VERSION 5.7 ;
BUSBITCHARS "[]" ;
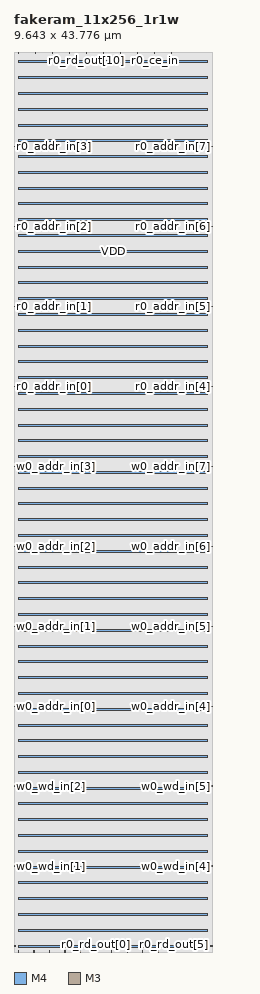
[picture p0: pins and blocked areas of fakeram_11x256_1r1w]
MACRO fakeram_11x256_1r1w
  FOREIGN fakeram_11x256_1r1w 0 0 ;
  SYMMETRY X Y R90 ;
  SIZE 9.643 BY 43.776 ;
  CLASS BLOCK ;
  PIN w0_wd_in[0]
    DIRECTION INPUT ;
    USE SIGNAL ;
    SHAPE ABUTMENT ;
    PORT
      LAYER M4 ;
      RECT 0.000 0.276 0.072 0.300 ;
    END
  END w0_wd_in[0]
  PIN w0_wd_in[1]
    DIRECTION INPUT ;
    USE SIGNAL ;
    SHAPE ABUTMENT ;
    PORT
      LAYER M4 ;
      RECT 0.000 4.164 0.072 4.188 ;
    END
  END w0_wd_in[1]
  PIN w0_wd_in[2]
    DIRECTION INPUT ;
    USE SIGNAL ;
    SHAPE ABUTMENT ;
    PORT
      LAYER M4 ;
      RECT 0.000 8.052 0.072 8.076 ;
    END
  END w0_wd_in[2]
  PIN w0_wd_in[3]
    DIRECTION INPUT ;
    USE SIGNAL ;
    SHAPE ABUTMENT ;
    PORT
      LAYER M4 ;
      RECT 9.571 0.276 9.643 0.300 ;
    END
  END w0_wd_in[3]
  PIN w0_wd_in[4]
    DIRECTION INPUT ;
    USE SIGNAL ;
    SHAPE ABUTMENT ;
    PORT
      LAYER M4 ;
      RECT 9.571 4.164 9.643 4.188 ;
    END
  END w0_wd_in[4]
  PIN w0_wd_in[5]
    DIRECTION INPUT ;
    USE SIGNAL ;
    SHAPE ABUTMENT ;
    PORT
      LAYER M4 ;
      RECT 9.571 8.052 9.643 8.076 ;
    END
  END w0_wd_in[5]
  PIN w0_wd_in[6]
    DIRECTION OUTPUT ;
    USE SIGNAL ;
    SHAPE ABUTMENT ;
    PORT
      LAYER M3 ;
      RECT 0.207 0.000 0.225 0.054 ;
    END
  END w0_wd_in[6]
  PIN w0_wd_in[7]
    DIRECTION OUTPUT ;
    USE SIGNAL ;
    SHAPE ABUTMENT ;
    PORT
      LAYER M3 ;
      RECT 0.963 0.000 0.981 0.054 ;
    END
  END w0_wd_in[7]
  PIN w0_wd_in[8]
    DIRECTION OUTPUT ;
    USE SIGNAL ;
    SHAPE ABUTMENT ;
    PORT
      LAYER M3 ;
      RECT 1.719 0.000 1.737 0.054 ;
    END
  END w0_wd_in[8]
  PIN w0_wd_in[9]
    DIRECTION OUTPUT ;
    USE SIGNAL ;
    SHAPE ABUTMENT ;
    PORT
      LAYER M3 ;
      RECT 2.475 0.000 2.493 0.054 ;
    END
  END w0_wd_in[9]
  PIN w0_wd_in[10]
    DIRECTION OUTPUT ;
    USE SIGNAL ;
    SHAPE ABUTMENT ;
    PORT
      LAYER M3 ;
      RECT 3.231 0.000 3.249 0.054 ;
    END
  END w0_wd_in[10]
  PIN r0_rd_out[0]
    DIRECTION OUTPUT ;
    USE SIGNAL ;
    SHAPE ABUTMENT ;
    PORT
      LAYER M3 ;
      RECT 3.987 0.000 4.005 0.054 ;
    END
  END r0_rd_out[0]
  PIN r0_rd_out[1]
    DIRECTION OUTPUT ;
    USE SIGNAL ;
    SHAPE ABUTMENT ;
    PORT
      LAYER M3 ;
      RECT 4.743 0.000 4.761 0.054 ;
    END
  END r0_rd_out[1]
  PIN r0_rd_out[2]
    DIRECTION OUTPUT ;
    USE SIGNAL ;
    SHAPE ABUTMENT ;
    PORT
      LAYER M3 ;
      RECT 5.499 0.000 5.517 0.054 ;
    END
  END r0_rd_out[2]
  PIN r0_rd_out[3]
    DIRECTION OUTPUT ;
    USE SIGNAL ;
    SHAPE ABUTMENT ;
    PORT
      LAYER M3 ;
      RECT 6.255 0.000 6.273 0.054 ;
    END
  END r0_rd_out[3]
  PIN r0_rd_out[4]
    DIRECTION OUTPUT ;
    USE SIGNAL ;
    SHAPE ABUTMENT ;
    PORT
      LAYER M3 ;
      RECT 7.011 0.000 7.029 0.054 ;
    END
  END r0_rd_out[4]
  PIN r0_rd_out[5]
    DIRECTION OUTPUT ;
    USE SIGNAL ;
    SHAPE ABUTMENT ;
    PORT
      LAYER M3 ;
      RECT 7.767 0.000 7.785 0.054 ;
    END
  END r0_rd_out[5]
  PIN r0_rd_out[6]
    DIRECTION OUTPUT ;
    USE SIGNAL ;
    SHAPE ABUTMENT ;
    PORT
      LAYER M3 ;
      RECT 0.207 43.722 0.225 43.776 ;
    END
  END r0_rd_out[6]
  PIN r0_rd_out[7]
    DIRECTION OUTPUT ;
    USE SIGNAL ;
    SHAPE ABUTMENT ;
    PORT
      LAYER M3 ;
      RECT 1.035 43.722 1.053 43.776 ;
    END
  END r0_rd_out[7]
  PIN r0_rd_out[8]
    DIRECTION OUTPUT ;
    USE SIGNAL ;
    SHAPE ABUTMENT ;
    PORT
      LAYER M3 ;
      RECT 1.863 43.722 1.881 43.776 ;
    END
  END r0_rd_out[8]
  PIN r0_rd_out[9]
    DIRECTION OUTPUT ;
    USE SIGNAL ;
    SHAPE ABUTMENT ;
    PORT
      LAYER M3 ;
      RECT 2.691 43.722 2.709 43.776 ;
    END
  END r0_rd_out[9]
  PIN r0_rd_out[10]
    DIRECTION OUTPUT ;
    USE SIGNAL ;
    SHAPE ABUTMENT ;
    PORT
      LAYER M3 ;
      RECT 3.519 43.722 3.537 43.776 ;
    END
  END r0_rd_out[10]
  PIN w0_addr_in[0]
    DIRECTION INPUT ;
    USE SIGNAL ;
    SHAPE ABUTMENT ;
    PORT
      LAYER M4 ;
      RECT 0.000 11.940 0.072 11.964 ;
    END
  END w0_addr_in[0]
  PIN w0_addr_in[1]
    DIRECTION INPUT ;
    USE SIGNAL ;
    SHAPE ABUTMENT ;
    PORT
      LAYER M4 ;
      RECT 0.000 15.828 0.072 15.852 ;
    END
  END w0_addr_in[1]
  PIN w0_addr_in[2]
    DIRECTION INPUT ;
    USE SIGNAL ;
    SHAPE ABUTMENT ;
    PORT
      LAYER M4 ;
      RECT 0.000 19.716 0.072 19.740 ;
    END
  END w0_addr_in[2]
  PIN w0_addr_in[3]
    DIRECTION INPUT ;
    USE SIGNAL ;
    SHAPE ABUTMENT ;
    PORT
      LAYER M4 ;
      RECT 0.000 23.604 0.072 23.628 ;
    END
  END w0_addr_in[3]
  PIN w0_addr_in[4]
    DIRECTION INPUT ;
    USE SIGNAL ;
    SHAPE ABUTMENT ;
    PORT
      LAYER M4 ;
      RECT 9.571 11.940 9.643 11.964 ;
    END
  END w0_addr_in[4]
  PIN w0_addr_in[5]
    DIRECTION INPUT ;
    USE SIGNAL ;
    SHAPE ABUTMENT ;
    PORT
      LAYER M4 ;
      RECT 9.571 15.828 9.643 15.852 ;
    END
  END w0_addr_in[5]
  PIN w0_addr_in[6]
    DIRECTION INPUT ;
    USE SIGNAL ;
    SHAPE ABUTMENT ;
    PORT
      LAYER M4 ;
      RECT 9.571 19.716 9.643 19.740 ;
    END
  END w0_addr_in[6]
  PIN w0_addr_in[7]
    DIRECTION INPUT ;
    USE SIGNAL ;
    SHAPE ABUTMENT ;
    PORT
      LAYER M4 ;
      RECT 9.571 23.604 9.643 23.628 ;
    END
  END w0_addr_in[7]
  PIN r0_addr_in[0]
    DIRECTION INPUT ;
    USE SIGNAL ;
    SHAPE ABUTMENT ;
    PORT
      LAYER M4 ;
      RECT 0.000 27.492 0.072 27.516 ;
    END
  END r0_addr_in[0]
  PIN r0_addr_in[1]
    DIRECTION INPUT ;
    USE SIGNAL ;
    SHAPE ABUTMENT ;
    PORT
      LAYER M4 ;
      RECT 0.000 31.380 0.072 31.404 ;
    END
  END r0_addr_in[1]
  PIN r0_addr_in[2]
    DIRECTION INPUT ;
    USE SIGNAL ;
    SHAPE ABUTMENT ;
    PORT
      LAYER M4 ;
      RECT 0.000 35.268 0.072 35.292 ;
    END
  END r0_addr_in[2]
  PIN r0_addr_in[3]
    DIRECTION INPUT ;
    USE SIGNAL ;
    SHAPE ABUTMENT ;
    PORT
      LAYER M4 ;
      RECT 0.000 39.156 0.072 39.180 ;
    END
  END r0_addr_in[3]
  PIN r0_addr_in[4]
    DIRECTION INPUT ;
    USE SIGNAL ;
    SHAPE ABUTMENT ;
    PORT
      LAYER M4 ;
      RECT 9.571 27.492 9.643 27.516 ;
    END
  END r0_addr_in[4]
  PIN r0_addr_in[5]
    DIRECTION INPUT ;
    USE SIGNAL ;
    SHAPE ABUTMENT ;
    PORT
      LAYER M4 ;
      RECT 9.571 31.380 9.643 31.404 ;
    END
  END r0_addr_in[5]
  PIN r0_addr_in[6]
    DIRECTION INPUT ;
    USE SIGNAL ;
    SHAPE ABUTMENT ;
    PORT
      LAYER M4 ;
      RECT 9.571 35.268 9.643 35.292 ;
    END
  END r0_addr_in[6]
  PIN r0_addr_in[7]
    DIRECTION INPUT ;
    USE SIGNAL ;
    SHAPE ABUTMENT ;
    PORT
      LAYER M4 ;
      RECT 9.571 39.156 9.643 39.180 ;
    END
  END r0_addr_in[7]
  PIN w0_we_in
    DIRECTION INPUT ;
    USE SIGNAL ;
    SHAPE ABUTMENT ;
    PORT
      LAYER M3 ;
      RECT 4.347 43.722 4.365 43.776 ;
    END
  END w0_we_in
  PIN w0_ce_in
    DIRECTION INPUT ;
    USE SIGNAL ;
    SHAPE ABUTMENT ;
    PORT
      LAYER M3 ;
      RECT 5.175 43.722 5.193 43.776 ;
    END
  END w0_ce_in
  PIN w0_clk
    DIRECTION INPUT ;
    USE SIGNAL ;
    SHAPE ABUTMENT ;
    PORT
      LAYER M3 ;
      RECT 6.003 43.722 6.021 43.776 ;
    END
  END w0_clk
  PIN r0_ce_in
    DIRECTION INPUT ;
    USE SIGNAL ;
    SHAPE ABUTMENT ;
    PORT
      LAYER M3 ;
      RECT 6.831 43.722 6.849 43.776 ;
    END
  END r0_ce_in
  PIN r0_clk
    DIRECTION INPUT ;
    USE SIGNAL ;
    SHAPE ABUTMENT ;
    PORT
      LAYER M3 ;
      RECT 7.659 43.722 7.677 43.776 ;
    END
  END r0_clk
  PIN VSS
    DIRECTION INOUT ;
    USE GROUND ;
    PORT
      LAYER M4 ;
      RECT 0.216 0.240 9.427 0.336 ;
      RECT 0.216 1.008 9.427 1.104 ;
      RECT 0.216 1.776 9.427 1.872 ;
      RECT 0.216 2.544 9.427 2.640 ;
      RECT 0.216 3.312 9.427 3.408 ;
      RECT 0.216 4.080 9.427 4.176 ;
      RECT 0.216 4.848 9.427 4.944 ;
      RECT 0.216 5.616 9.427 5.712 ;
      RECT 0.216 6.384 9.427 6.480 ;
      RECT 0.216 7.152 9.427 7.248 ;
      RECT 0.216 7.920 9.427 8.016 ;
      RECT 0.216 8.688 9.427 8.784 ;
      RECT 0.216 9.456 9.427 9.552 ;
      RECT 0.216 10.224 9.427 10.320 ;
      RECT 0.216 10.992 9.427 11.088 ;
      RECT 0.216 11.760 9.427 11.856 ;
      RECT 0.216 12.528 9.427 12.624 ;
      RECT 0.216 13.296 9.427 13.392 ;
      RECT 0.216 14.064 9.427 14.160 ;
      RECT 0.216 14.832 9.427 14.928 ;
      RECT 0.216 15.600 9.427 15.696 ;
      RECT 0.216 16.368 9.427 16.464 ;
      RECT 0.216 17.136 9.427 17.232 ;
      RECT 0.216 17.904 9.427 18.000 ;
      RECT 0.216 18.672 9.427 18.768 ;
      RECT 0.216 19.440 9.427 19.536 ;
      RECT 0.216 20.208 9.427 20.304 ;
      RECT 0.216 20.976 9.427 21.072 ;
      RECT 0.216 21.744 9.427 21.840 ;
      RECT 0.216 22.512 9.427 22.608 ;
      RECT 0.216 23.280 9.427 23.376 ;
      RECT 0.216 24.048 9.427 24.144 ;
      RECT 0.216 24.816 9.427 24.912 ;
      RECT 0.216 25.584 9.427 25.680 ;
      RECT 0.216 26.352 9.427 26.448 ;
      RECT 0.216 27.120 9.427 27.216 ;
      RECT 0.216 27.888 9.427 27.984 ;
      RECT 0.216 28.656 9.427 28.752 ;
      RECT 0.216 29.424 9.427 29.520 ;
      RECT 0.216 30.192 9.427 30.288 ;
      RECT 0.216 30.960 9.427 31.056 ;
      RECT 0.216 31.728 9.427 31.824 ;
      RECT 0.216 32.496 9.427 32.592 ;
      RECT 0.216 33.264 9.427 33.360 ;
      RECT 0.216 34.032 9.427 34.128 ;
      RECT 0.216 34.800 9.427 34.896 ;
      RECT 0.216 35.568 9.427 35.664 ;
      RECT 0.216 36.336 9.427 36.432 ;
      RECT 0.216 37.104 9.427 37.200 ;
      RECT 0.216 37.872 9.427 37.968 ;
      RECT 0.216 38.640 9.427 38.736 ;
      RECT 0.216 39.408 9.427 39.504 ;
      RECT 0.216 40.176 9.427 40.272 ;
      RECT 0.216 40.944 9.427 41.040 ;
      RECT 0.216 41.712 9.427 41.808 ;
      RECT 0.216 42.480 9.427 42.576 ;
      RECT 0.216 43.248 9.427 43.344 ;
    END
  END VSS
  PIN VDD
    DIRECTION INOUT ;
    USE POWER ;
    PORT
      LAYER M4 ;
      RECT 0.216 0.240 9.427 0.336 ;
      RECT 0.216 1.008 9.427 1.104 ;
      RECT 0.216 1.776 9.427 1.872 ;
      RECT 0.216 2.544 9.427 2.640 ;
      RECT 0.216 3.312 9.427 3.408 ;
      RECT 0.216 4.080 9.427 4.176 ;
      RECT 0.216 4.848 9.427 4.944 ;
      RECT 0.216 5.616 9.427 5.712 ;
      RECT 0.216 6.384 9.427 6.480 ;
      RECT 0.216 7.152 9.427 7.248 ;
      RECT 0.216 7.920 9.427 8.016 ;
      RECT 0.216 8.688 9.427 8.784 ;
      RECT 0.216 9.456 9.427 9.552 ;
      RECT 0.216 10.224 9.427 10.320 ;
      RECT 0.216 10.992 9.427 11.088 ;
      RECT 0.216 11.760 9.427 11.856 ;
      RECT 0.216 12.528 9.427 12.624 ;
      RECT 0.216 13.296 9.427 13.392 ;
      RECT 0.216 14.064 9.427 14.160 ;
      RECT 0.216 14.832 9.427 14.928 ;
      RECT 0.216 15.600 9.427 15.696 ;
      RECT 0.216 16.368 9.427 16.464 ;
      RECT 0.216 17.136 9.427 17.232 ;
      RECT 0.216 17.904 9.427 18.000 ;
      RECT 0.216 18.672 9.427 18.768 ;
      RECT 0.216 19.440 9.427 19.536 ;
      RECT 0.216 20.208 9.427 20.304 ;
      RECT 0.216 20.976 9.427 21.072 ;
      RECT 0.216 21.744 9.427 21.840 ;
      RECT 0.216 22.512 9.427 22.608 ;
      RECT 0.216 23.280 9.427 23.376 ;
      RECT 0.216 24.048 9.427 24.144 ;
      RECT 0.216 24.816 9.427 24.912 ;
      RECT 0.216 25.584 9.427 25.680 ;
      RECT 0.216 26.352 9.427 26.448 ;
      RECT 0.216 27.120 9.427 27.216 ;
      RECT 0.216 27.888 9.427 27.984 ;
      RECT 0.216 28.656 9.427 28.752 ;
      RECT 0.216 29.424 9.427 29.520 ;
      RECT 0.216 30.192 9.427 30.288 ;
      RECT 0.216 30.960 9.427 31.056 ;
      RECT 0.216 31.728 9.427 31.824 ;
      RECT 0.216 32.496 9.427 32.592 ;
      RECT 0.216 33.264 9.427 33.360 ;
      RECT 0.216 34.032 9.427 34.128 ;
      RECT 0.216 34.800 9.427 34.896 ;
      RECT 0.216 35.568 9.427 35.664 ;
      RECT 0.216 36.336 9.427 36.432 ;
      RECT 0.216 37.104 9.427 37.200 ;
      RECT 0.216 37.872 9.427 37.968 ;
      RECT 0.216 38.640 9.427 38.736 ;
      RECT 0.216 39.408 9.427 39.504 ;
      RECT 0.216 40.176 9.427 40.272 ;
      RECT 0.216 40.944 9.427 41.040 ;
      RECT 0.216 41.712 9.427 41.808 ;
      RECT 0.216 42.480 9.427 42.576 ;
      RECT 0.216 43.248 9.427 43.344 ;
    END
  END VDD
  OBS
    LAYER M1 ;
    RECT 0 0 9.643 43.776 ;
    LAYER M2 ;
    RECT 0 0 9.643 43.776 ;
    LAYER M3 ;
    RECT 0 0 9.643 43.776 ;
    LAYER M4 ;
    RECT 0 0 9.643 43.776 ;
  END
END fakeram_11x256_1r1w

END LIBRARY
